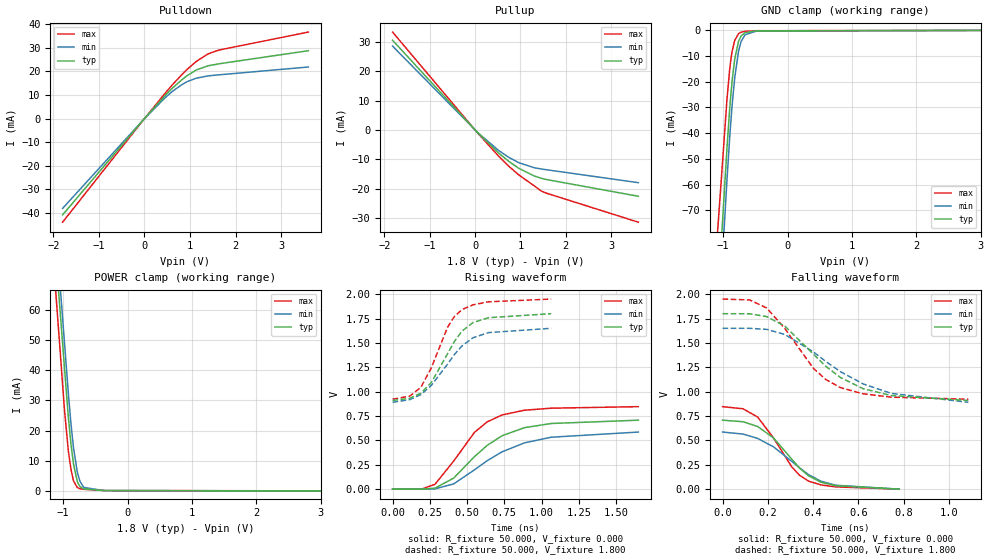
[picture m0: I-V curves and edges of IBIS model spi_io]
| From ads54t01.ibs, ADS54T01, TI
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[Model]   spi_io
Model_type I/O
Vinl=5.400E-01
Vinh=1.260E+00
Vref=0.000E+00
Rref=1.000E+06
Cref=0.000E+00
Vmeas=9.000E-01
C_comp   1.110E-12   1.050E-12   1.160E-12
[Voltage Range]   1.800E+00   1.650E+00   1.950E+00
[POWER Clamp Reference]   1.800E+00   1.650E+00   1.950E+00
[GND Clamp Reference]   0.000E+00   0.000E+00   0.000E+00
[Pullup Reference]   1.800E+00   1.650E+00   1.950E+00
[Pulldown Reference]   0.000E+00   0.000E+00   0.000E+00
[Temperature Range]   25   85   -40
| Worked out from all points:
|   slope of the pulldown table from 0 to 0.27 V, typ, clamps not added: 45.7 ohm
|   slope of the pullup table from 0 to 0.27 V, typ, clamps not added: 63.8 ohm
|   GND clamp passes 1 mA (typ) near -0.67 V on its own axis
|   POWER clamp passes 1 mA (typ) near -0.72 V on its own axis
|   rising waveform, R_fixture 50.000, V_fixture 0.000: 20-80 % time 330ps typ, 394ps min, 265ps max; typ from 0 V to 0.708 V
|   falling waveform, R_fixture 50.000, V_fixture 0.000: 20-80 % time 172ps typ, 201ps min, 148ps max; typ from 0.708 V to 0 V
|   rising waveform, R_fixture 50.000, V_fixture 1.800: 20-80 % time 209ps typ, 240ps min, 178ps max; typ from 0.909 V to 1.8 V
|   falling waveform, R_fixture 50.000, V_fixture 1.800: 20-80 % time 263ps typ, 313ps min, 210ps max; typ from 1.8 V to 0.909 V
[GND Clamp]
-1.8V     -399.7mA   -427.2mA   -328.5mA
-1.02V    -78.8mA    -92.48mA   -55.06mA
-940mV    -45.64mA   -57.96mA   -26.64mA
-900mV    -31.13mA   -42.36mA   -15.54mA
-880mV    -24.93mA   -35.38mA   -11.36mA
-860mV    -19.51mA   -29.02mA   -8.094mA
-820mV    -11.13mA   -18.4mA    -3.893mA
-760mV    -4.175mA   -8.006mA   -1.294mA
-720mV    -2.11mA    -4.27mA    -688.8uA
-660mV    -894.6uA   -1.733mA   -393.8uA
-480mV    -192.1uA   -261.5uA   -150uA
3.6V      0A         0A         0A
[Power Clamp]
-1.8V     268.3mA    279.3mA    264.6mA
-1.08V    68.73mA    77.19mA    55.83mA
-1.06V    63.19mA    71.6mA     50.21mA
-980mV    40.95mA    49.32mA    26.99mA
-920mV    24.65mA    32.47mA    13.37mA
-880mV    15.75mA    22.59mA    7.305mA
-840mV    8.965mA    14.43mA    3.386mA
-780mV    3.08mA     6.18mA     1.107mA
-740mV    1.455mA    3.231mA    731.7uA
-680mV    669.2uA    1.169mA    538.5uA
-360mV    115uA      85.18uA    143.6uA
3.6V      0A         0A         0A
[Pullup]
-1.82V    30.48mA    28.48mA    33.25mA
60mV      -985.1uA   -897.5uA   -1.089mA
520mV     -7.836mA   -6.963mA   -8.887mA
740mV     -10.6mA    -9.251mA   -12.27mA
960mV     -12.97mA   -11.07mA   -15.21mA
1.3V      -15.59mA   -12.79mA   -18.92mA
1.46V     -16.39mA   -13.24mA   -20.73mA
1.56V     -16.77mA   -13.46mA   -21.38mA
3.6V      -22.5mA    -17.88mA   -31.3mA
[Pulldown]
-1.8V     -40.85mA   -38.1mA    -43.94mA
0V        0A         0A         0A
460mV     9.892mA    8.953mA    10.89mA
620mV     13.01mA    11.62mA    14.47mA
820mV     16.44mA    14.36mA    18.59mA
940mV     18.25mA    15.67mA    20.93mA
1.14V     20.62mA    17.14mA    24.24mA
1.4V      22.39mA    18.1mA     27.46mA
1.64V     23.23mA    18.54mA    29.06mA
3.6V      28.77mA    21.86mA    36.66mA
[Rising Waveform]
R_fixture = 50.000
V_fixture = 0.000
V_fixture_min = 0.000
V_fixture_max = 0.000
|  time   V(typ)   V(min)   V(max)
0s        0V         0V         0V
200ps     233.2uV    9.218uV    3.926mV
285ps     10.49mV    3.216mV    49.94mV
410ps     113.2mV    53.73mV    287.8mV
550ps     333.6mV    198.4mV    583.1mV
635ps     449mV      291.7mV    690.1mV
735ps     547.8mV    382.8mV    761.3mV
885ps     630.6mV    474.7mV    809.8mV
1.065ns   673.6mV    532.8mV    830.6mV
1.65ns    707.6mV    585.8mV    846.4mV
[Falling Waveform]
R_fixture = 50.000
V_fixture = 0.000
V_fixture_min = 0.000
V_fixture_max = 0.000
|  time   V(typ)   V(min)   V(max)
0s        707.6mV    585.8mV    846.4mV
90ps      691.8mV    565.3mV    824.7mV
155ps     643mV      520.6mV    740mV
225ps     525.3mV    433.5mV    524.6mV
305ps     309.2mV    286.4mV    230.2mV
340ps     216.5mV    218.4mV    142.3mV
380ps     136.2mV    148.8mV    82.04mV
435ps     70.67mV    80.67mV    43.26mV
500ps     35.66mV    40.26mV    23.43mV
780ps     0V         0V         0V
[Rising Waveform]
R_fixture = 50.000
V_fixture = 1.800
V_fixture_min = 1.650
V_fixture_max = 1.950
|  time   V(typ)   V(min)   V(max)
0s        909.5mV    891.2mV    923mV
115ps     931.8mV    918.1mV    954.1mV
190ps     984.3mV    970.7mV    1.045V
260ps     1.094V     1.064V     1.244V
370ps     1.391V     1.284V     1.663V
415ps     1.515V     1.381V     1.771V
465ps     1.62V      1.468V     1.841V
540ps     1.709V     1.553V     1.891V
645ps     1.759V     1.606V     1.922V
1.065ns   1.8V       1.65V      1.95V
[Falling Waveform]
R_fixture = 50.000
V_fixture = 1.800
V_fixture_min = 1.650
V_fixture_max = 1.950
|  time   V(typ)   V(min)   V(max)
0s        1.8V       1.65V      1.95V
120ps     1.799V     1.65V      1.941V
195ps     1.77V      1.639V     1.858V
275ps     1.672V     1.587V     1.648V
400ps     1.387V     1.41V      1.242V
455ps     1.262V     1.311V     1.126V
520ps     1.146V     1.206V     1.042V
620ps     1.031V     1.08V      978.2mV
745ps     959.9mV    982.3mV    943.6mV
1.085ns   909.5mV    891.2mV    923mV
[Ramp]
dV/dt_r   4.2465E-01/3.2978E-10   3.5115E-01/3.9418E-10   5.0625E-01/2.6313E-10
dV/dt_f   5.3433E-01/2.6197E-10   4.5531E-01/3.1264E-10   6.1619E-01/2.0979E-10
R_load = 50
